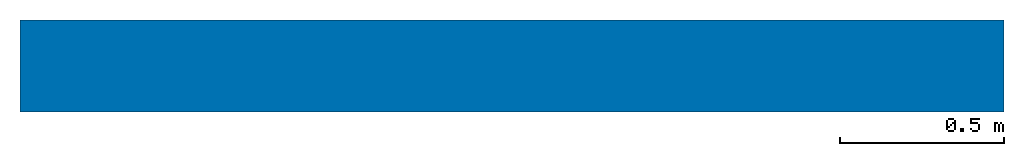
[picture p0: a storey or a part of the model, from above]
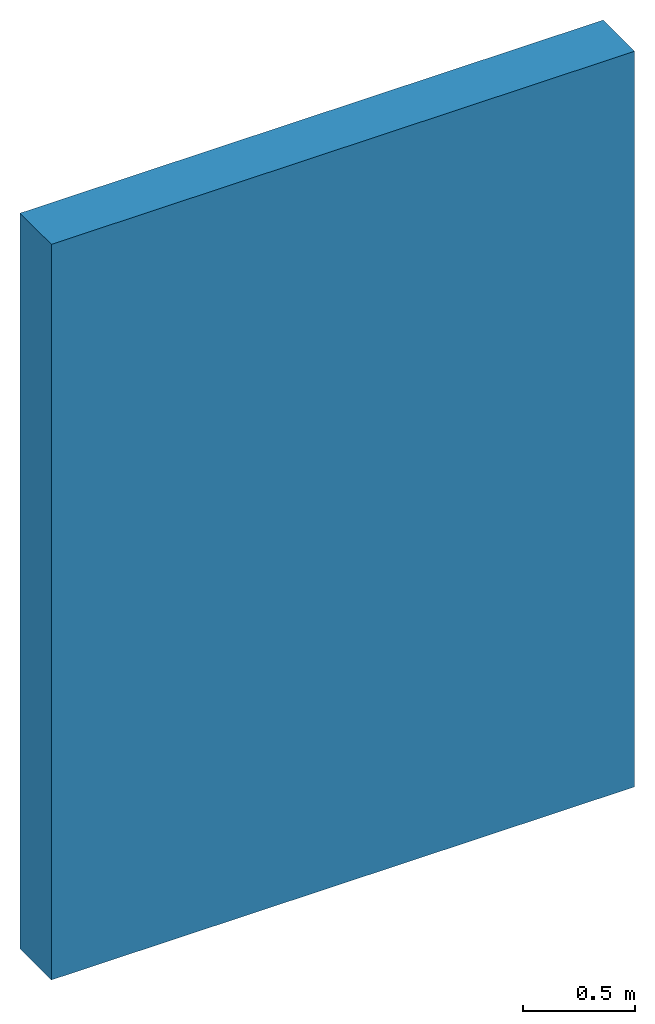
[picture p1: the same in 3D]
Properties of the parts of a building model (IFC2X3)

# File
Description: ViewDefinition [CoordinationView_V2.0, QuantityTakeOffAddOnView]
File name: 0001
Time: 2018-04-04T18:26:05
Written by: The EXPRESS Data Manager Version 5.02.0100.07 : 28 Aug 2013
Made in: 20170419_0315(x64) - Exporter 17.0.1128.0 - Альтернативный интерфейс 17.17.0.0
Comment: STEP Physical File produced by: The EXPRESS Data Manager Version 5.02.0100.07 : 28 Aug 2013 * Module: EDMstepFileFactory/EDMstandAlone * Creation date: Wed Apr 04 18:26:05 2018 * Host: w13mim038 * Database: C:\Users\odegov.s\AppData\Local\Temp\{8A19C065-A828-491D-93A2-661040686367}\ifc * Database version: 5507 * Database creation date: Wed Apr 04 18:26:05 2018 * Schema: IFC2X3 * Model: DataRepository.ifc * Model creation date: Wed Apr 04 18:26:05 2018 * Header model: DataRepository.ifc_HeaderModel * Header model creation date: Wed Apr 04 18:26:05 2018 * EDMuser: sdai-user * EDMgroup: sdai-group * License ID and type: 5605 : Permanent license. Expiry date: * EDMstepFileFactory options: 020000

# IfcProject, 0001
LongName: Наименование проекта; Phase: Статус проекта

# IfcSite, Default
RefLatitude: 55, 44, 59, 999999; RefLongitude: 37, 42, 0, 2746; RefElevation: 0 mm
Прочее - Адрес проекта: Укажите адрес; Дата утверждения проекта: Дата выпуска; Заказчик: Владелец; Категория: Сведения о проекте; Наименование проекта: Наименование проекта; Номер проекта: 0001; Статус проекта: Статус проекта

# IfcBuilding
Pset_BuildingCommon - NumberOfStoreys: 1
Прочее - Категория: Сведения о проекте; Адрес проекта: Укажите адрес; Дата утверждения проекта: Дата выпуска; Заказчик: Владелец; Наименование проекта: Наименование проекта; Номер проекта: 0001; Статус проекта: Статус проекта

# IfcBuildingStorey, Уровень 1
LongName: Уровень 1; Elevation: 0 mm
Прочее - Категория: Уровни; Имя семейства: Уровень; Код типа: Уровень: Верхний брус 8 мм; Семейство: Уровень: Верхний брус 8 мм; Семейство и типоразмер: Уровень: Верхний брус 8 мм; Тип: Уровень: Верхний брус 8 мм
Зависимости - Фасад: 0 mm; Базовая отметка: Базовая точка проекта
Идентификация - Несущие конструкции: no; Имя: Уровень 1; Построение этажа: yes; Имя типа: Верхний брус 8 мм
Размеры - Расчетная высота: 0 mm
Графика - Вес линий: 1; Обозначение: Заголовок уровня - Окружность: Заголовок уровня - Окружность; Образец линий: Центр; Стандартное обозначение второго конца: yes; Стандартное обозначение первого конца: no; Цвет: 0

# IfcWallStandardCase: Базовая стена:Перегородка КНАУФ ПГП 100 Применение внутри здания Двойная ПлГ 100, Базовая стена:Перегородка КНАУФ ПГП 100 Применение внутри здания Двойная ПлГ 100:423007
In: Уровень 1
Type - PredefinedType: STANDARD; Material: Кнауф-Плита пазогребневая 100 mm, Luft 80 mm, Кнауф-Плита пазогребневая 100 mm
Type - Графика - Цвет штриховки при низкой детализации: 0
Type - Идентификация - Имя типа: Перегородка КНАУФ ПГП 100 Применение внутри здания Двойная ПлГ 100
Type - Материалы и отделка - Материал несущих конструкций: Кнауф-Плита пазогребневая
Type - Прочее - Категория: Стены; Имя семейства: Базовая стена
Type - Свойства аналитической модели - Коэффициент поглощения: 0.7; Коэффициент теплопередачи (U): 0.3125; Теплоемкость: 96.336; Термостойкость: 3.2; Шероховатость: 3
Type - Строительство - Огибание в местах вставки элементов: Нет; Огибание в торцах стен: Нет; Функция: Внутренние слои; Ширина: 280 mm
BaseQuantities - Height: 4000 mm; Length: 3000 mm; Width: 280 mm; GrossFootprintArea: 0.84 m2; GrossSideArea: 12 m2; GrossVolume: 3.36 m3
Зависимости - Базовая зависимость: Уровень: Уровень 1; Граница помещения: yes; Линия привязки: Осевая линия стены; Неприсоединенная высота: 4000 mm; Примыкание сверху: no; Примыкание снизу: no; Размер выступа сверху: 0 mm; Размер выступа снизу: 0 mm; Связь с формообразующим элементом: no; Смещение сверху: 0 mm; Смещение снизу: 0 mm
Несущие конструкции - Включить аналитическую модель: no; Использование в конструкции: Ненесущая; Несущие конструкции: no
Прочее - Код типа: Базовая стена: Перегородка КНАУФ ПГП 100 Применение внутри здания Двойная ПлГ 100; Семейство: Базовая стена: Перегородка КНАУФ ПГП 100 Применение внутри здания Двойная ПлГ 100; Семейство и типоразмер: Базовая стена: Перегородка КНАУФ ПГП 100 Применение внутри здания Двойная ПлГ 100; Тип: Базовая стена: Перегородка КНАУФ ПГП 100 Применение внутри здания Двойная ПлГ 100
Размеры - Длина: 3000 mm; Объем: 3.36 m3; Площадь: 12 m2
Стадии - Стадия возведения: Новая конструкция
Pset_WallCommon - Reference: Перегородка КНАУФ ПГП 100 Применение внутри здания Двойная ПлГ 100; LoadBearing: no; ExtendToStructure: no; IsExternal: no; ThermalTransmittance: 0.3125 kg/K/s3
